VERSION 5.7 ;
  NOWIREEXTENSIONATPIN ON ;
  DIVIDERCHAR "/" ;
  BUSBITCHARS "[]" ;
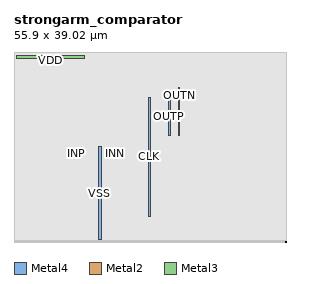
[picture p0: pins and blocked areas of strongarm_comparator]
MACRO strongarm_comparator
  CLASS BLOCK ;
  FOREIGN strongarm_comparator ;
  ORIGIN 28.060 4.240 ;
  SIZE 55.900 BY 39.020 ;
  PIN OUTN
    ANTENNAGATEAREA 5.538000 ;
    ANTENNADIFFAREA 4.669200 ;
    PORT
      LAYER Metal4 ;
        RECT 5.740 17.600 6.020 27.520 ;
    END
  END OUTN
  PIN OUTP
    ANTENNAGATEAREA 5.538000 ;
    ANTENNADIFFAREA 4.669200 ;
    PORT
      LAYER Metal4 ;
        RECT 3.700 17.600 3.980 25.480 ;
    END
  END OUTP
  PIN CLK
    ANTENNAGATEAREA 11.112000 ;
    PORT
      LAYER Metal4 ;
        RECT -0.380 1.000 -0.100 25.480 ;
    END
  END CLK
  PIN INN
    ANTENNAGATEAREA 2.088000 ;
    PORT
      LAYER Metal2 ;
        RECT -7.550 13.710 -7.270 13.990 ;
    END
  END INN
  PIN INP
    ANTENNAGATEAREA 2.088000 ;
    PORT
      LAYER Metal2 ;
        RECT -15.330 13.710 -15.050 13.990 ;
    END
  END INP
  PIN VSS
    USE GROUND ;
    PORT
      LAYER Metal4 ;
        RECT -10.720 -3.820 -10.160 15.280 ;
    END
  END VSS
  PIN VDD
    USE POWER ;
    PORT
      LAYER Metal3 ;
        RECT -27.640 33.500 -13.640 34.060 ;
    END
  END VDD
  OBS
      LAYER Nwell ;
        RECT -24.840 0.000 24.840 30.750 ;
      LAYER Metal1 ;
        RECT -24.610 0.210 24.610 30.540 ;
      LAYER Metal2 ;
        RECT -24.610 14.290 24.610 30.540 ;
        RECT -24.610 13.410 -15.630 14.290 ;
        RECT -14.750 13.410 -7.850 14.290 ;
        RECT -6.970 13.410 24.610 14.290 ;
        RECT -24.610 0.210 24.610 13.410 ;
      LAYER Metal3 ;
        RECT -28.060 33.920 -27.640 34.060 ;
        RECT -28.060 33.640 -27.920 33.920 ;
        RECT -28.060 33.500 -27.640 33.640 ;
        RECT -28.060 33.200 -27.940 33.500 ;
        RECT -13.340 33.200 27.580 34.060 ;
        RECT -28.060 -4.240 27.580 33.200 ;
      LAYER Metal4 ;
        RECT -28.030 27.820 27.550 34.030 ;
        RECT -28.030 25.780 5.440 27.820 ;
        RECT -28.030 15.580 -0.680 25.780 ;
        RECT -28.030 -4.120 -11.020 15.580 ;
        RECT -9.860 0.700 -0.680 15.580 ;
        RECT 0.200 17.300 3.400 25.780 ;
        RECT 4.280 17.300 5.440 25.780 ;
        RECT 6.320 17.300 27.550 27.820 ;
        RECT 0.200 0.700 27.550 17.300 ;
        RECT -9.860 -4.120 27.550 0.700 ;
        RECT -28.030 -4.240 27.550 -4.120 ;
      LAYER Metal5 ;
        RECT -28.030 -3.940 27.840 34.780 ;
  END
END strongarm_comparator
END LIBRARY

